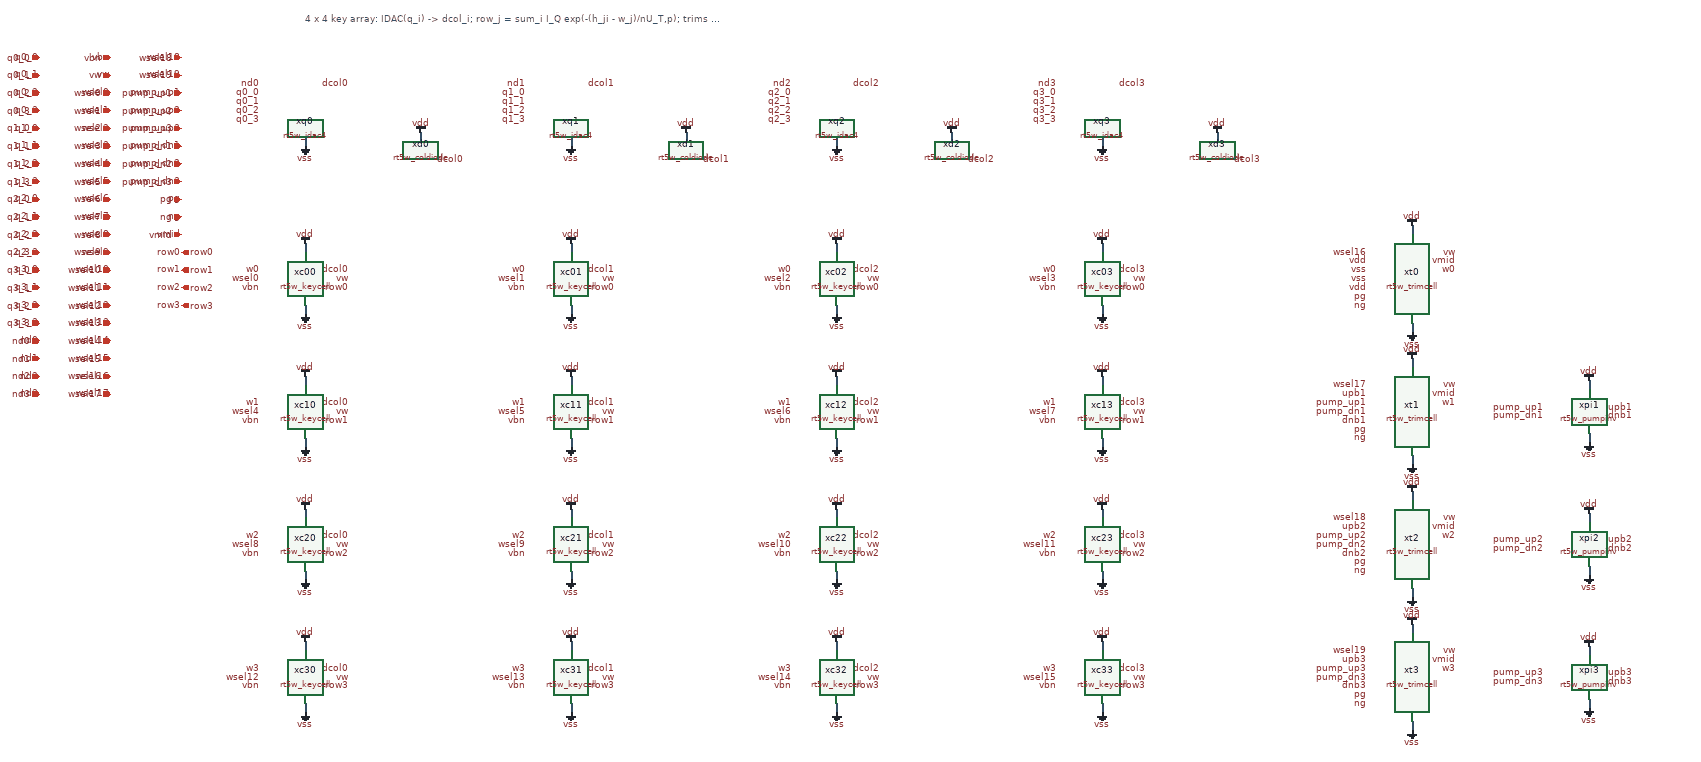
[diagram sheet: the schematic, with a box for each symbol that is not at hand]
v {xschem version=3.4.5 file_version=1.2}
G {}
K {}
V {}
S {}
E {}
T {4 x 4 key array: IDAC(q_i) -> dcol_i;  row_j = sum_i I_Q exp(-(h_ji - w_j)/nU_T,p);  trims w_j} 0 -900 0 0 0.6 0.6 {}
N 0 -620 0 -600 {lab=vss}
C {gnd.sym} 0 -600 0 0 {name=r1 lab=vss}
N 0 -240 0 -220 {lab=vss}
C {gnd.sym} 0 -220 0 0 {name=r2 lab=vss}
N 0 60 0 80 {lab=vss}
C {gnd.sym} 0 80 0 0 {name=r3 lab=vss}
N 0 360 0 380 {lab=vss}
C {gnd.sym} 0 380 0 0 {name=r4 lab=vss}
N 0 660 0 680 {lab=vss}
C {gnd.sym} 0 680 0 0 {name=r5 lab=vss}
N 600 -620 600 -600 {lab=vss}
C {gnd.sym} 600 -600 0 0 {name=r6 lab=vss}
N 600 -240 600 -220 {lab=vss}
C {gnd.sym} 600 -220 0 0 {name=r7 lab=vss}
N 600 60 600 80 {lab=vss}
C {gnd.sym} 600 80 0 0 {name=r8 lab=vss}
N 600 360 600 380 {lab=vss}
C {gnd.sym} 600 380 0 0 {name=r9 lab=vss}
N 600 660 600 680 {lab=vss}
C {gnd.sym} 600 680 0 0 {name=r10 lab=vss}
N 1200 -620 1200 -600 {lab=vss}
C {gnd.sym} 1200 -600 0 0 {name=r11 lab=vss}
N 1200 -240 1200 -220 {lab=vss}
C {gnd.sym} 1200 -220 0 0 {name=r12 lab=vss}
N 1200 60 1200 80 {lab=vss}
C {gnd.sym} 1200 80 0 0 {name=r13 lab=vss}
N 1200 360 1200 380 {lab=vss}
C {gnd.sym} 1200 380 0 0 {name=r14 lab=vss}
N 1200 660 1200 680 {lab=vss}
C {gnd.sym} 1200 680 0 0 {name=r15 lab=vss}
N 1800 -620 1800 -600 {lab=vss}
C {gnd.sym} 1800 -600 0 0 {name=r16 lab=vss}
N 1800 -240 1800 -220 {lab=vss}
C {gnd.sym} 1800 -220 0 0 {name=r17 lab=vss}
N 1800 60 1800 80 {lab=vss}
C {gnd.sym} 1800 80 0 0 {name=r18 lab=vss}
N 1800 360 1800 380 {lab=vss}
C {gnd.sym} 1800 380 0 0 {name=r19 lab=vss}
N 1800 660 1800 680 {lab=vss}
C {gnd.sym} 1800 680 0 0 {name=r20 lab=vss}
N 2500 -200 2500 -180 {lab=vss}
C {gnd.sym} 2500 -180 0 0 {name=r21 lab=vss}
N 2500 100 2500 120 {lab=vss}
C {gnd.sym} 2500 120 0 0 {name=r22 lab=vss}
N 2500 400 2500 420 {lab=vss}
C {gnd.sym} 2500 420 0 0 {name=r23 lab=vss}
N 2500 700 2500 720 {lab=vss}
C {gnd.sym} 2500 720 0 0 {name=r24 lab=vss}
N 2900 50 2900 70 {lab=vss}
C {gnd.sym} 2900 70 0 0 {name=r25 lab=vss}
N 2900 350 2900 370 {lab=vss}
C {gnd.sym} 2900 370 0 0 {name=r26 lab=vss}
N 2900 650 2900 670 {lab=vss}
C {gnd.sym} 2900 670 0 0 {name=r27 lab=vss}
N 0 -360 0 -380 {lab=vdd}
C {vdd.sym} 0 -380 0 0 {name=r28 lab=vdd}
N 0 -60 0 -80 {lab=vdd}
C {vdd.sym} 0 -80 0 0 {name=r29 lab=vdd}
N 0 240 0 220 {lab=vdd}
C {vdd.sym} 0 220 0 0 {name=r30 lab=vdd}
N 0 540 0 520 {lab=vdd}
C {vdd.sym} 0 520 0 0 {name=r31 lab=vdd}
N 260 -610 260 -630 {lab=vdd}
C {vdd.sym} 260 -630 0 0 {name=r32 lab=vdd}
N 600 -360 600 -380 {lab=vdd}
C {vdd.sym} 600 -380 0 0 {name=r33 lab=vdd}
N 600 -60 600 -80 {lab=vdd}
C {vdd.sym} 600 -80 0 0 {name=r34 lab=vdd}
N 600 240 600 220 {lab=vdd}
C {vdd.sym} 600 220 0 0 {name=r35 lab=vdd}
N 600 540 600 520 {lab=vdd}
C {vdd.sym} 600 520 0 0 {name=r36 lab=vdd}
N 860 -610 860 -630 {lab=vdd}
C {vdd.sym} 860 -630 0 0 {name=r37 lab=vdd}
N 1200 -360 1200 -380 {lab=vdd}
C {vdd.sym} 1200 -380 0 0 {name=r38 lab=vdd}
N 1200 -60 1200 -80 {lab=vdd}
C {vdd.sym} 1200 -80 0 0 {name=r39 lab=vdd}
N 1200 240 1200 220 {lab=vdd}
C {vdd.sym} 1200 220 0 0 {name=r40 lab=vdd}
N 1200 540 1200 520 {lab=vdd}
C {vdd.sym} 1200 520 0 0 {name=r41 lab=vdd}
N 1460 -610 1460 -630 {lab=vdd}
C {vdd.sym} 1460 -630 0 0 {name=r42 lab=vdd}
N 1800 -360 1800 -380 {lab=vdd}
C {vdd.sym} 1800 -380 0 0 {name=r43 lab=vdd}
N 1800 -60 1800 -80 {lab=vdd}
C {vdd.sym} 1800 -80 0 0 {name=r44 lab=vdd}
N 1800 240 1800 220 {lab=vdd}
C {vdd.sym} 1800 220 0 0 {name=r45 lab=vdd}
N 1800 540 1800 520 {lab=vdd}
C {vdd.sym} 1800 520 0 0 {name=r46 lab=vdd}
N 2060 -610 2060 -630 {lab=vdd}
C {vdd.sym} 2060 -630 0 0 {name=r47 lab=vdd}
N 2500 -400 2500 -420 {lab=vdd}
C {vdd.sym} 2500 -420 0 0 {name=r48 lab=vdd}
N 2500 -100 2500 -120 {lab=vdd}
C {vdd.sym} 2500 -120 0 0 {name=r49 lab=vdd}
N 2500 200 2500 180 {lab=vdd}
C {vdd.sym} 2500 180 0 0 {name=r50 lab=vdd}
N 2500 500 2500 480 {lab=vdd}
C {vdd.sym} 2500 480 0 0 {name=r51 lab=vdd}
N 2900 -50 2900 -70 {lab=vdd}
C {vdd.sym} 2900 -70 0 0 {name=r52 lab=vdd}
N 2900 250 2900 230 {lab=vdd}
C {vdd.sym} 2900 230 0 0 {name=r53 lab=vdd}
N 2900 550 2900 530 {lab=vdd}
C {vdd.sym} 2900 530 0 0 {name=r54 lab=vdd}
C {lab_pin.sym} 2400 -300 0 0 {name=l55 sig_type=std_logic lab=vss}
C {lab_pin.sym} 2400 -340 0 0 {name=l56 sig_type=std_logic lab=vdd}
C {lab_pin.sym} 2400 -280 0 0 {name=l57 sig_type=std_logic lab=vdd}
C {lab_pin.sym} 2400 -320 0 0 {name=l58 sig_type=std_logic lab=vss}
C {lab_pin.sym} -600 -160 0 0 {name=l59 sig_type=std_logic lab=nd0}
C {lab_pin.sym} -100 -740 0 0 {name=l60 sig_type=std_logic lab=nd0}
C {lab_pin.sym} -600 -800 0 0 {name=l61 sig_type=std_logic lab=q0_0}
C {lab_pin.sym} -100 -720 0 0 {name=l62 sig_type=std_logic lab=q0_0}
C {lab_pin.sym} -600 -760 0 0 {name=l63 sig_type=std_logic lab=q0_1}
C {lab_pin.sym} -100 -700 0 0 {name=l64 sig_type=std_logic lab=q0_1}
C {lab_pin.sym} -600 -720 0 0 {name=l65 sig_type=std_logic lab=q0_2}
C {lab_pin.sym} -100 -680 0 0 {name=l66 sig_type=std_logic lab=q0_2}
C {lab_pin.sym} -600 -680 0 0 {name=l67 sig_type=std_logic lab=q0_3}
C {lab_pin.sym} -100 -660 0 0 {name=l68 sig_type=std_logic lab=q0_3}
C {lab_pin.sym} -440 -720 0 0 {name=l69 sig_type=std_logic lab=wsel0}
C {lab_pin.sym} -100 -300 0 0 {name=l70 sig_type=std_logic lab=wsel0}
C {lab_pin.sym} -440 -560 0 0 {name=l71 sig_type=std_logic lab=wsel4}
C {lab_pin.sym} -100 0 0 0 {name=l72 sig_type=std_logic lab=wsel4}
C {lab_pin.sym} -440 -400 0 0 {name=l73 sig_type=std_logic lab=wsel8}
C {lab_pin.sym} -100 300 0 0 {name=l74 sig_type=std_logic lab=wsel8}
C {lab_pin.sym} -440 -240 0 0 {name=l75 sig_type=std_logic lab=wsel12}
C {lab_pin.sym} -100 600 0 0 {name=l76 sig_type=std_logic lab=wsel12}
C {lab_pin.sym} -600 -120 0 0 {name=l77 sig_type=std_logic lab=nd1}
C {lab_pin.sym} 500 -740 0 0 {name=l78 sig_type=std_logic lab=nd1}
C {lab_pin.sym} -600 -640 0 0 {name=l79 sig_type=std_logic lab=q1_0}
C {lab_pin.sym} 500 -720 0 0 {name=l80 sig_type=std_logic lab=q1_0}
C {lab_pin.sym} -600 -600 0 0 {name=l81 sig_type=std_logic lab=q1_1}
C {lab_pin.sym} 500 -700 0 0 {name=l82 sig_type=std_logic lab=q1_1}
C {lab_pin.sym} -600 -560 0 0 {name=l83 sig_type=std_logic lab=q1_2}
C {lab_pin.sym} 500 -680 0 0 {name=l84 sig_type=std_logic lab=q1_2}
C {lab_pin.sym} -600 -520 0 0 {name=l85 sig_type=std_logic lab=q1_3}
C {lab_pin.sym} 500 -660 0 0 {name=l86 sig_type=std_logic lab=q1_3}
C {lab_pin.sym} -440 -680 0 0 {name=l87 sig_type=std_logic lab=wsel1}
C {lab_pin.sym} 500 -300 0 0 {name=l88 sig_type=std_logic lab=wsel1}
C {lab_pin.sym} -440 -520 0 0 {name=l89 sig_type=std_logic lab=wsel5}
C {lab_pin.sym} 500 0 0 0 {name=l90 sig_type=std_logic lab=wsel5}
C {lab_pin.sym} -440 -360 0 0 {name=l91 sig_type=std_logic lab=wsel9}
C {lab_pin.sym} 500 300 0 0 {name=l92 sig_type=std_logic lab=wsel9}
C {lab_pin.sym} -440 -200 0 0 {name=l93 sig_type=std_logic lab=wsel13}
C {lab_pin.sym} 500 600 0 0 {name=l94 sig_type=std_logic lab=wsel13}
C {lab_pin.sym} -600 -80 0 0 {name=l95 sig_type=std_logic lab=nd2}
C {lab_pin.sym} 1100 -740 0 0 {name=l96 sig_type=std_logic lab=nd2}
C {lab_pin.sym} -600 -480 0 0 {name=l97 sig_type=std_logic lab=q2_0}
C {lab_pin.sym} 1100 -720 0 0 {name=l98 sig_type=std_logic lab=q2_0}
C {lab_pin.sym} -600 -440 0 0 {name=l99 sig_type=std_logic lab=q2_1}
C {lab_pin.sym} 1100 -700 0 0 {name=l100 sig_type=std_logic lab=q2_1}
C {lab_pin.sym} -600 -400 0 0 {name=l101 sig_type=std_logic lab=q2_2}
C {lab_pin.sym} 1100 -680 0 0 {name=l102 sig_type=std_logic lab=q2_2}
C {lab_pin.sym} -600 -360 0 0 {name=l103 sig_type=std_logic lab=q2_3}
C {lab_pin.sym} 1100 -660 0 0 {name=l104 sig_type=std_logic lab=q2_3}
C {lab_pin.sym} -440 -640 0 0 {name=l105 sig_type=std_logic lab=wsel2}
C {lab_pin.sym} 1100 -300 0 0 {name=l106 sig_type=std_logic lab=wsel2}
C {lab_pin.sym} -440 -480 0 0 {name=l107 sig_type=std_logic lab=wsel6}
C {lab_pin.sym} 1100 0 0 0 {name=l108 sig_type=std_logic lab=wsel6}
C {lab_pin.sym} -440 -320 0 0 {name=l109 sig_type=std_logic lab=wsel10}
C {lab_pin.sym} 1100 300 0 0 {name=l110 sig_type=std_logic lab=wsel10}
C {lab_pin.sym} -440 -160 0 0 {name=l111 sig_type=std_logic lab=wsel14}
C {lab_pin.sym} 1100 600 0 0 {name=l112 sig_type=std_logic lab=wsel14}
C {lab_pin.sym} -600 -40 0 0 {name=l113 sig_type=std_logic lab=nd3}
C {lab_pin.sym} 1700 -740 0 0 {name=l114 sig_type=std_logic lab=nd3}
C {lab_pin.sym} -600 -320 0 0 {name=l115 sig_type=std_logic lab=q3_0}
C {lab_pin.sym} 1700 -720 0 0 {name=l116 sig_type=std_logic lab=q3_0}
C {lab_pin.sym} -600 -280 0 0 {name=l117 sig_type=std_logic lab=q3_1}
C {lab_pin.sym} 1700 -700 0 0 {name=l118 sig_type=std_logic lab=q3_1}
C {lab_pin.sym} -600 -240 0 0 {name=l119 sig_type=std_logic lab=q3_2}
C {lab_pin.sym} 1700 -680 0 0 {name=l120 sig_type=std_logic lab=q3_2}
C {lab_pin.sym} -600 -200 0 0 {name=l121 sig_type=std_logic lab=q3_3}
C {lab_pin.sym} 1700 -660 0 0 {name=l122 sig_type=std_logic lab=q3_3}
C {lab_pin.sym} -440 -600 0 0 {name=l123 sig_type=std_logic lab=wsel3}
C {lab_pin.sym} 1700 -300 0 0 {name=l124 sig_type=std_logic lab=wsel3}
C {lab_pin.sym} -440 -440 0 0 {name=l125 sig_type=std_logic lab=wsel7}
C {lab_pin.sym} 1700 0 0 0 {name=l126 sig_type=std_logic lab=wsel7}
C {lab_pin.sym} -440 -280 0 0 {name=l127 sig_type=std_logic lab=wsel11}
C {lab_pin.sym} 1700 300 0 0 {name=l128 sig_type=std_logic lab=wsel11}
C {lab_pin.sym} -440 -120 0 0 {name=l129 sig_type=std_logic lab=wsel15}
C {lab_pin.sym} 1700 600 0 0 {name=l130 sig_type=std_logic lab=wsel15}
C {lab_pin.sym} -440 -80 0 0 {name=l131 sig_type=std_logic lab=wsel16}
C {lab_pin.sym} 2400 -360 0 0 {name=l132 sig_type=std_logic lab=wsel16}
C {lab_pin.sym} 2400 -40 0 0 {name=l133 sig_type=std_logic lab=upb1}
C {lab_pin.sym} 3000 -10 0 0 {name=l134 sig_type=std_logic lab=upb1}
C {lab_pin.sym} 2400 20 0 0 {name=l135 sig_type=std_logic lab=dnb1}
C {lab_pin.sym} 3000 10 0 0 {name=l136 sig_type=std_logic lab=dnb1}
C {lab_pin.sym} -440 -40 0 0 {name=l137 sig_type=std_logic lab=wsel17}
C {lab_pin.sym} 2400 -60 0 0 {name=l138 sig_type=std_logic lab=wsel17}
C {lab_pin.sym} 2400 260 0 0 {name=l139 sig_type=std_logic lab=upb2}
C {lab_pin.sym} 3000 290 0 0 {name=l140 sig_type=std_logic lab=upb2}
C {lab_pin.sym} 2400 320 0 0 {name=l141 sig_type=std_logic lab=dnb2}
C {lab_pin.sym} 3000 310 0 0 {name=l142 sig_type=std_logic lab=dnb2}
C {lab_pin.sym} -280 -800 0 0 {name=l143 sig_type=std_logic lab=wsel18}
C {lab_pin.sym} 2400 240 0 0 {name=l144 sig_type=std_logic lab=wsel18}
C {lab_pin.sym} 2400 560 0 0 {name=l145 sig_type=std_logic lab=upb3}
C {lab_pin.sym} 3000 590 0 0 {name=l146 sig_type=std_logic lab=upb3}
C {lab_pin.sym} 2400 620 0 0 {name=l147 sig_type=std_logic lab=dnb3}
C {lab_pin.sym} 3000 610 0 0 {name=l148 sig_type=std_logic lab=dnb3}
C {lab_pin.sym} -280 -760 0 0 {name=l149 sig_type=std_logic lab=wsel19}
C {lab_pin.sym} 2400 540 0 0 {name=l150 sig_type=std_logic lab=wsel19}
C {lab_pin.sym} -280 -720 0 0 {name=l151 sig_type=std_logic lab=pump_up1}
C {lab_pin.sym} 2400 -20 0 0 {name=l152 sig_type=std_logic lab=pump_up1}
C {lab_pin.sym} 2800 -10 0 0 {name=l153 sig_type=std_logic lab=pump_up1}
C {lab_pin.sym} -280 -600 0 0 {name=l154 sig_type=std_logic lab=pump_dn1}
C {lab_pin.sym} 2400 0 0 0 {name=l155 sig_type=std_logic lab=pump_dn1}
C {lab_pin.sym} 2800 10 0 0 {name=l156 sig_type=std_logic lab=pump_dn1}
C {lab_pin.sym} -280 -680 0 0 {name=l157 sig_type=std_logic lab=pump_up2}
C {lab_pin.sym} 2400 280 0 0 {name=l158 sig_type=std_logic lab=pump_up2}
C {lab_pin.sym} 2800 290 0 0 {name=l159 sig_type=std_logic lab=pump_up2}
C {lab_pin.sym} -280 -560 0 0 {name=l160 sig_type=std_logic lab=pump_dn2}
C {lab_pin.sym} 2400 300 0 0 {name=l161 sig_type=std_logic lab=pump_dn2}
C {lab_pin.sym} 2800 310 0 0 {name=l162 sig_type=std_logic lab=pump_dn2}
C {lab_pin.sym} -280 -640 0 0 {name=l163 sig_type=std_logic lab=pump_up3}
C {lab_pin.sym} 2400 580 0 0 {name=l164 sig_type=std_logic lab=pump_up3}
C {lab_pin.sym} 2800 590 0 0 {name=l165 sig_type=std_logic lab=pump_up3}
C {lab_pin.sym} -280 -520 0 0 {name=l166 sig_type=std_logic lab=pump_dn3}
C {lab_pin.sym} 2400 600 0 0 {name=l167 sig_type=std_logic lab=pump_dn3}
C {lab_pin.sym} 2800 610 0 0 {name=l168 sig_type=std_logic lab=pump_dn3}
C {lab_pin.sym} -100 -320 0 0 {name=l169 sig_type=std_logic lab=w0}
C {lab_pin.sym} 500 -320 0 0 {name=l170 sig_type=std_logic lab=w0}
C {lab_pin.sym} 1100 -320 0 0 {name=l171 sig_type=std_logic lab=w0}
C {lab_pin.sym} 1700 -320 0 0 {name=l172 sig_type=std_logic lab=w0}
C {lab_pin.sym} 2600 -320 0 0 {name=l173 sig_type=std_logic lab=w0}
C {lab_pin.sym} -280 -360 0 0 {name=l174 sig_type=std_logic lab=row0}
C {lab_pin.sym} 100 -280 0 0 {name=l175 sig_type=std_logic lab=row0}
C {lab_pin.sym} 700 -280 0 0 {name=l176 sig_type=std_logic lab=row0}
C {lab_pin.sym} 1300 -280 0 0 {name=l177 sig_type=std_logic lab=row0}
C {lab_pin.sym} 1900 -280 0 0 {name=l178 sig_type=std_logic lab=row0}
C {lab_pin.sym} -100 -20 0 0 {name=l179 sig_type=std_logic lab=w1}
C {lab_pin.sym} 500 -20 0 0 {name=l180 sig_type=std_logic lab=w1}
C {lab_pin.sym} 1100 -20 0 0 {name=l181 sig_type=std_logic lab=w1}
C {lab_pin.sym} 1700 -20 0 0 {name=l182 sig_type=std_logic lab=w1}
C {lab_pin.sym} 2600 -20 0 0 {name=l183 sig_type=std_logic lab=w1}
C {lab_pin.sym} -280 -320 0 0 {name=l184 sig_type=std_logic lab=row1}
C {lab_pin.sym} 100 20 0 0 {name=l185 sig_type=std_logic lab=row1}
C {lab_pin.sym} 700 20 0 0 {name=l186 sig_type=std_logic lab=row1}
C {lab_pin.sym} 1300 20 0 0 {name=l187 sig_type=std_logic lab=row1}
C {lab_pin.sym} 1900 20 0 0 {name=l188 sig_type=std_logic lab=row1}
C {lab_pin.sym} -100 280 0 0 {name=l189 sig_type=std_logic lab=w2}
C {lab_pin.sym} 500 280 0 0 {name=l190 sig_type=std_logic lab=w2}
C {lab_pin.sym} 1100 280 0 0 {name=l191 sig_type=std_logic lab=w2}
C {lab_pin.sym} 1700 280 0 0 {name=l192 sig_type=std_logic lab=w2}
C {lab_pin.sym} 2600 280 0 0 {name=l193 sig_type=std_logic lab=w2}
C {lab_pin.sym} -280 -280 0 0 {name=l194 sig_type=std_logic lab=row2}
C {lab_pin.sym} 100 320 0 0 {name=l195 sig_type=std_logic lab=row2}
C {lab_pin.sym} 700 320 0 0 {name=l196 sig_type=std_logic lab=row2}
C {lab_pin.sym} 1300 320 0 0 {name=l197 sig_type=std_logic lab=row2}
C {lab_pin.sym} 1900 320 0 0 {name=l198 sig_type=std_logic lab=row2}
C {lab_pin.sym} -100 580 0 0 {name=l199 sig_type=std_logic lab=w3}
C {lab_pin.sym} 500 580 0 0 {name=l200 sig_type=std_logic lab=w3}
C {lab_pin.sym} 1100 580 0 0 {name=l201 sig_type=std_logic lab=w3}
C {lab_pin.sym} 1700 580 0 0 {name=l202 sig_type=std_logic lab=w3}
C {lab_pin.sym} 2600 580 0 0 {name=l203 sig_type=std_logic lab=w3}
C {lab_pin.sym} -280 -240 0 0 {name=l204 sig_type=std_logic lab=row3}
C {lab_pin.sym} 100 620 0 0 {name=l205 sig_type=std_logic lab=row3}
C {lab_pin.sym} 700 620 0 0 {name=l206 sig_type=std_logic lab=row3}
C {lab_pin.sym} 1300 620 0 0 {name=l207 sig_type=std_logic lab=row3}
C {lab_pin.sym} 1900 620 0 0 {name=l208 sig_type=std_logic lab=row3}
C {lab_pin.sym} -280 -480 0 0 {name=l209 sig_type=std_logic lab=pg}
C {lab_pin.sym} 2400 -260 0 0 {name=l210 sig_type=std_logic lab=pg}
C {lab_pin.sym} 2400 40 0 0 {name=l211 sig_type=std_logic lab=pg}
C {lab_pin.sym} 2400 340 0 0 {name=l212 sig_type=std_logic lab=pg}
C {lab_pin.sym} 2400 640 0 0 {name=l213 sig_type=std_logic lab=pg}
C {lab_pin.sym} -280 -440 0 0 {name=l214 sig_type=std_logic lab=ng}
C {lab_pin.sym} 2400 -240 0 0 {name=l215 sig_type=std_logic lab=ng}
C {lab_pin.sym} 2400 60 0 0 {name=l216 sig_type=std_logic lab=ng}
C {lab_pin.sym} 2400 360 0 0 {name=l217 sig_type=std_logic lab=ng}
C {lab_pin.sym} 2400 660 0 0 {name=l218 sig_type=std_logic lab=ng}
C {lab_pin.sym} -280 -400 0 0 {name=l219 sig_type=std_logic lab=vmid}
C {lab_pin.sym} 2600 -340 0 0 {name=l220 sig_type=std_logic lab=vmid}
C {lab_pin.sym} 2600 -40 0 0 {name=l221 sig_type=std_logic lab=vmid}
C {lab_pin.sym} 2600 260 0 0 {name=l222 sig_type=std_logic lab=vmid}
C {lab_pin.sym} 2600 560 0 0 {name=l223 sig_type=std_logic lab=vmid}
C {lab_pin.sym} 100 -740 0 0 {name=l224 sig_type=std_logic lab=dcol0}
C {lab_pin.sym} 100 -320 0 0 {name=l225 sig_type=std_logic lab=dcol0}
C {lab_pin.sym} 100 -20 0 0 {name=l226 sig_type=std_logic lab=dcol0}
C {lab_pin.sym} 100 280 0 0 {name=l227 sig_type=std_logic lab=dcol0}
C {lab_pin.sym} 100 580 0 0 {name=l228 sig_type=std_logic lab=dcol0}
C {lab_pin.sym} 360 -570 0 0 {name=l229 sig_type=std_logic lab=dcol0}
C {lab_pin.sym} 700 -740 0 0 {name=l230 sig_type=std_logic lab=dcol1}
C {lab_pin.sym} 700 -320 0 0 {name=l231 sig_type=std_logic lab=dcol1}
C {lab_pin.sym} 700 -20 0 0 {name=l232 sig_type=std_logic lab=dcol1}
C {lab_pin.sym} 700 280 0 0 {name=l233 sig_type=std_logic lab=dcol1}
C {lab_pin.sym} 700 580 0 0 {name=l234 sig_type=std_logic lab=dcol1}
C {lab_pin.sym} 960 -570 0 0 {name=l235 sig_type=std_logic lab=dcol1}
C {lab_pin.sym} 1300 -740 0 0 {name=l236 sig_type=std_logic lab=dcol2}
C {lab_pin.sym} 1300 -320 0 0 {name=l237 sig_type=std_logic lab=dcol2}
C {lab_pin.sym} 1300 -20 0 0 {name=l238 sig_type=std_logic lab=dcol2}
C {lab_pin.sym} 1300 280 0 0 {name=l239 sig_type=std_logic lab=dcol2}
C {lab_pin.sym} 1300 580 0 0 {name=l240 sig_type=std_logic lab=dcol2}
C {lab_pin.sym} 1560 -570 0 0 {name=l241 sig_type=std_logic lab=dcol2}
C {lab_pin.sym} 1900 -740 0 0 {name=l242 sig_type=std_logic lab=dcol3}
C {lab_pin.sym} 1900 -320 0 0 {name=l243 sig_type=std_logic lab=dcol3}
C {lab_pin.sym} 1900 -20 0 0 {name=l244 sig_type=std_logic lab=dcol3}
C {lab_pin.sym} 1900 280 0 0 {name=l245 sig_type=std_logic lab=dcol3}
C {lab_pin.sym} 1900 580 0 0 {name=l246 sig_type=std_logic lab=dcol3}
C {lab_pin.sym} 2160 -570 0 0 {name=l247 sig_type=std_logic lab=dcol3}
C {lab_pin.sym} -440 -800 0 0 {name=l248 sig_type=std_logic lab=vbn}
C {lab_pin.sym} -100 -280 0 0 {name=l249 sig_type=std_logic lab=vbn}
C {lab_pin.sym} -100 20 0 0 {name=l250 sig_type=std_logic lab=vbn}
C {lab_pin.sym} -100 320 0 0 {name=l251 sig_type=std_logic lab=vbn}
C {lab_pin.sym} -100 620 0 0 {name=l252 sig_type=std_logic lab=vbn}
C {lab_pin.sym} 500 -280 0 0 {name=l253 sig_type=std_logic lab=vbn}
C {lab_pin.sym} 500 20 0 0 {name=l254 sig_type=std_logic lab=vbn}
C {lab_pin.sym} 500 320 0 0 {name=l255 sig_type=std_logic lab=vbn}
C {lab_pin.sym} 500 620 0 0 {name=l256 sig_type=std_logic lab=vbn}
C {lab_pin.sym} 1100 -280 0 0 {name=l257 sig_type=std_logic lab=vbn}
C {lab_pin.sym} 1100 20 0 0 {name=l258 sig_type=std_logic lab=vbn}
C {lab_pin.sym} 1100 320 0 0 {name=l259 sig_type=std_logic lab=vbn}
C {lab_pin.sym} 1100 620 0 0 {name=l260 sig_type=std_logic lab=vbn}
C {lab_pin.sym} 1700 -280 0 0 {name=l261 sig_type=std_logic lab=vbn}
C {lab_pin.sym} 1700 20 0 0 {name=l262 sig_type=std_logic lab=vbn}
C {lab_pin.sym} 1700 320 0 0 {name=l263 sig_type=std_logic lab=vbn}
C {lab_pin.sym} 1700 620 0 0 {name=l264 sig_type=std_logic lab=vbn}
C {lab_pin.sym} -440 -760 0 0 {name=l265 sig_type=std_logic lab=vw}
C {lab_pin.sym} 100 -300 0 0 {name=l266 sig_type=std_logic lab=vw}
C {lab_pin.sym} 100 0 0 0 {name=l267 sig_type=std_logic lab=vw}
C {lab_pin.sym} 100 300 0 0 {name=l268 sig_type=std_logic lab=vw}
C {lab_pin.sym} 100 600 0 0 {name=l269 sig_type=std_logic lab=vw}
C {lab_pin.sym} 700 -300 0 0 {name=l270 sig_type=std_logic lab=vw}
C {lab_pin.sym} 700 0 0 0 {name=l271 sig_type=std_logic lab=vw}
C {lab_pin.sym} 700 300 0 0 {name=l272 sig_type=std_logic lab=vw}
C {lab_pin.sym} 700 600 0 0 {name=l273 sig_type=std_logic lab=vw}
C {lab_pin.sym} 1300 -300 0 0 {name=l274 sig_type=std_logic lab=vw}
C {lab_pin.sym} 1300 0 0 0 {name=l275 sig_type=std_logic lab=vw}
C {lab_pin.sym} 1300 300 0 0 {name=l276 sig_type=std_logic lab=vw}
C {lab_pin.sym} 1300 600 0 0 {name=l277 sig_type=std_logic lab=vw}
C {lab_pin.sym} 1900 -300 0 0 {name=l278 sig_type=std_logic lab=vw}
C {lab_pin.sym} 1900 0 0 0 {name=l279 sig_type=std_logic lab=vw}
C {lab_pin.sym} 1900 300 0 0 {name=l280 sig_type=std_logic lab=vw}
C {lab_pin.sym} 1900 600 0 0 {name=l281 sig_type=std_logic lab=vw}
C {lab_pin.sym} 2600 -360 0 0 {name=l282 sig_type=std_logic lab=vw}
C {lab_pin.sym} 2600 -60 0 0 {name=l283 sig_type=std_logic lab=vw}
C {lab_pin.sym} 2600 240 0 0 {name=l284 sig_type=std_logic lab=vw}
C {lab_pin.sym} 2600 540 0 0 {name=l285 sig_type=std_logic lab=vw}
C {ipin.sym} -600 -800 0 0 {name=p286 lab=q0_0}
C {ipin.sym} -600 -760 0 0 {name=p287 lab=q0_1}
C {ipin.sym} -600 -720 0 0 {name=p288 lab=q0_2}
C {ipin.sym} -600 -680 0 0 {name=p289 lab=q0_3}
C {ipin.sym} -600 -640 0 0 {name=p290 lab=q1_0}
C {ipin.sym} -600 -600 0 0 {name=p291 lab=q1_1}
C {ipin.sym} -600 -560 0 0 {name=p292 lab=q1_2}
C {ipin.sym} -600 -520 0 0 {name=p293 lab=q1_3}
C {ipin.sym} -600 -480 0 0 {name=p294 lab=q2_0}
C {ipin.sym} -600 -440 0 0 {name=p295 lab=q2_1}
C {ipin.sym} -600 -400 0 0 {name=p296 lab=q2_2}
C {ipin.sym} -600 -360 0 0 {name=p297 lab=q2_3}
C {ipin.sym} -600 -320 0 0 {name=p298 lab=q3_0}
C {ipin.sym} -600 -280 0 0 {name=p299 lab=q3_1}
C {ipin.sym} -600 -240 0 0 {name=p300 lab=q3_2}
C {ipin.sym} -600 -200 0 0 {name=p301 lab=q3_3}
C {ipin.sym} -600 -160 0 0 {name=p302 lab=nd0}
C {ipin.sym} -600 -120 0 0 {name=p303 lab=nd1}
C {ipin.sym} -600 -80 0 0 {name=p304 lab=nd2}
C {ipin.sym} -600 -40 0 0 {name=p305 lab=nd3}
C {ipin.sym} -440 -800 0 0 {name=p306 lab=vbn}
C {iopin.sym} -440 -760 0 0 {name=p307 lab=vw}
C {ipin.sym} -440 -720 0 0 {name=p308 lab=wsel0}
C {ipin.sym} -440 -680 0 0 {name=p309 lab=wsel1}
C {ipin.sym} -440 -640 0 0 {name=p310 lab=wsel2}
C {ipin.sym} -440 -600 0 0 {name=p311 lab=wsel3}
C {ipin.sym} -440 -560 0 0 {name=p312 lab=wsel4}
C {ipin.sym} -440 -520 0 0 {name=p313 lab=wsel5}
C {ipin.sym} -440 -480 0 0 {name=p314 lab=wsel6}
C {ipin.sym} -440 -440 0 0 {name=p315 lab=wsel7}
C {ipin.sym} -440 -400 0 0 {name=p316 lab=wsel8}
C {ipin.sym} -440 -360 0 0 {name=p317 lab=wsel9}
C {ipin.sym} -440 -320 0 0 {name=p318 lab=wsel10}
C {ipin.sym} -440 -280 0 0 {name=p319 lab=wsel11}
C {ipin.sym} -440 -240 0 0 {name=p320 lab=wsel12}
C {ipin.sym} -440 -200 0 0 {name=p321 lab=wsel13}
C {ipin.sym} -440 -160 0 0 {name=p322 lab=wsel14}
C {ipin.sym} -440 -120 0 0 {name=p323 lab=wsel15}
C {ipin.sym} -440 -80 0 0 {name=p324 lab=wsel16}
C {ipin.sym} -440 -40 0 0 {name=p325 lab=wsel17}
C {ipin.sym} -280 -800 0 0 {name=p326 lab=wsel18}
C {ipin.sym} -280 -760 0 0 {name=p327 lab=wsel19}
C {ipin.sym} -280 -720 0 0 {name=p328 lab=pump_up1}
C {ipin.sym} -280 -680 0 0 {name=p329 lab=pump_up2}
C {ipin.sym} -280 -640 0 0 {name=p330 lab=pump_up3}
C {ipin.sym} -280 -600 0 0 {name=p331 lab=pump_dn1}
C {ipin.sym} -280 -560 0 0 {name=p332 lab=pump_dn2}
C {ipin.sym} -280 -520 0 0 {name=p333 lab=pump_dn3}
C {ipin.sym} -280 -480 0 0 {name=p334 lab=pg}
C {ipin.sym} -280 -440 0 0 {name=p335 lab=ng}
C {ipin.sym} -280 -400 0 0 {name=p336 lab=vmid}
C {opin.sym} -280 -360 0 0 {name=p337 lab=row0}
C {opin.sym} -280 -320 0 0 {name=p338 lab=row1}
C {opin.sym} -280 -280 0 0 {name=p339 lab=row2}
C {opin.sym} -280 -240 0 0 {name=p340 lab=row3}
C {rt5w_idac4.sym} 0 -700 0 0 {name=xq0}
C {rt5w_coldiode.sym} 260 -560 0 0 {name=xd0}
C {rt5w_keycell.sym} 0 -300 0 0 {name=xc00}
C {rt5w_keycell.sym} 0 0 0 0 {name=xc10}
C {rt5w_keycell.sym} 0 300 0 0 {name=xc20}
C {rt5w_keycell.sym} 0 600 0 0 {name=xc30}
C {rt5w_idac4.sym} 600 -700 0 0 {name=xq1}
C {rt5w_coldiode.sym} 860 -560 0 0 {name=xd1}
C {rt5w_keycell.sym} 600 -300 0 0 {name=xc01}
C {rt5w_keycell.sym} 600 0 0 0 {name=xc11}
C {rt5w_keycell.sym} 600 300 0 0 {name=xc21}
C {rt5w_keycell.sym} 600 600 0 0 {name=xc31}
C {rt5w_idac4.sym} 1200 -700 0 0 {name=xq2}
C {rt5w_coldiode.sym} 1460 -560 0 0 {name=xd2}
C {rt5w_keycell.sym} 1200 -300 0 0 {name=xc02}
C {rt5w_keycell.sym} 1200 0 0 0 {name=xc12}
C {rt5w_keycell.sym} 1200 300 0 0 {name=xc22}
C {rt5w_keycell.sym} 1200 600 0 0 {name=xc32}
C {rt5w_idac4.sym} 1800 -700 0 0 {name=xq3}
C {rt5w_coldiode.sym} 2060 -560 0 0 {name=xd3}
C {rt5w_keycell.sym} 1800 -300 0 0 {name=xc03}
C {rt5w_keycell.sym} 1800 0 0 0 {name=xc13}
C {rt5w_keycell.sym} 1800 300 0 0 {name=xc23}
C {rt5w_keycell.sym} 1800 600 0 0 {name=xc33}
C {rt5w_trimcell.sym} 2500 -300 0 0 {name=xt0}
C {rt5w_pumpinv.sym} 2900 0 0 0 {name=xpi1}
C {rt5w_trimcell.sym} 2500 0 0 0 {name=xt1}
C {rt5w_pumpinv.sym} 2900 300 0 0 {name=xpi2}
C {rt5w_trimcell.sym} 2500 300 0 0 {name=xt2}
C {rt5w_pumpinv.sym} 2900 600 0 0 {name=xpi3}
C {rt5w_trimcell.sym} 2500 600 0 0 {name=xt3}
